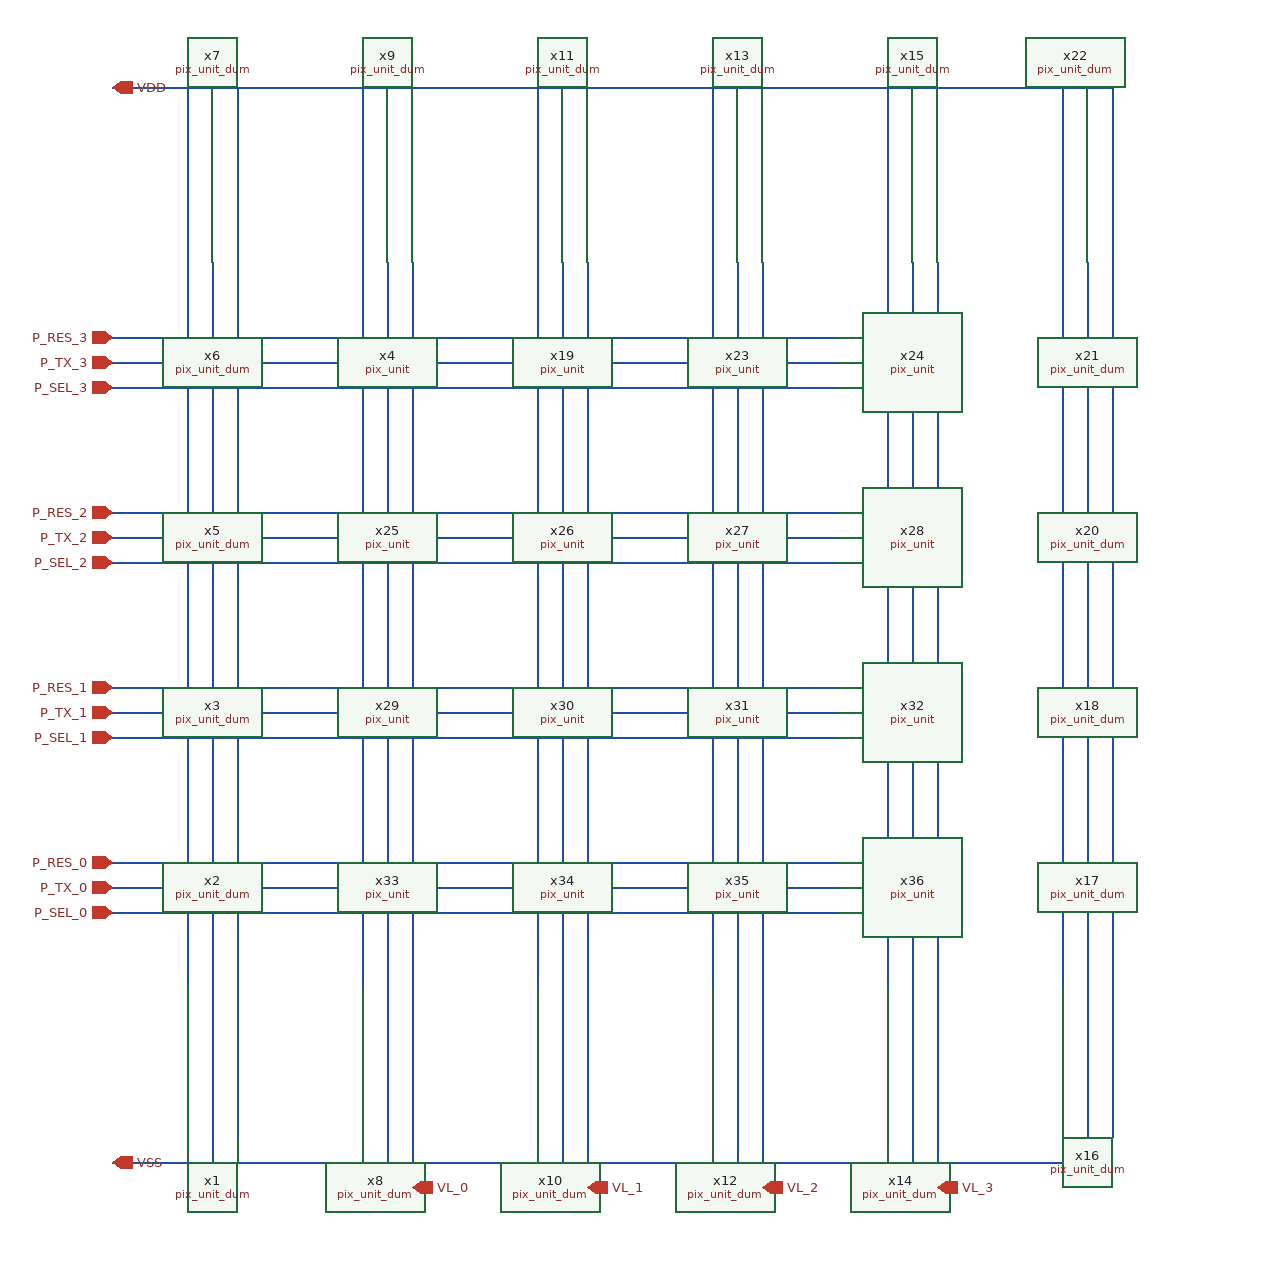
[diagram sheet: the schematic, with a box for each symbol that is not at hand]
v {xschem version=3.4.8RC file_version=1.2}
G {}
K {}
V {}
S {}
E {}
N 180 -960 180 -240 {lab=VDD}
N 320 -960 320 -240 {lab=VDD}
N 460 -960 460 -240 {lab=VDD}
N 600 -960 600 -240 {lab=VDD}
N 740 -960 740 -240 {lab=VDD}
N 880 -960 880 -240 {lab=VDD}
N 120 -960 920 -960 {lab=VDD}
N 200 -820 200 -100 {lab=VSS}
N 340 -820 340 -100 {lab=VSS}
N 480 -820 480 -100 {lab=VSS}
N 620 -820 620 -100 {lab=VSS}
N 760 -820 760 -100 {lab=VSS}
N 900 -820 900 -100 {lab=VSS}
N 120 -100 900 -100 {lab=VSS}
N 220 -960 220 -120 {lab=VDD}
N 920 -960 920 -120 {lab=VDD}
N 360 -820 360 -80 {lab=VL_0}
N 500 -820 500 -80 {lab=VL_1}
N 640 -820 640 -80 {lab=VL_2}
N 780 -820 780 -80 {lab=VL_3}
N 120 -760 700 -760 {lab=P_RES_3}
N 120 -740 700 -740 {lab=P_TX_3}
N 120 -720 700 -720 {lab=P_SEL_3}
N 120 -620 700 -620 {lab=P_RES_2}
N 120 -600 700 -600 {lab=P_TX_2}
N 120 -580 700 -580 {lab=P_SEL_2}
N 120 -480 700 -480 {lab=P_RES_1}
N 120 -460 700 -460 {lab=P_TX_1}
N 120 -440 700 -440 {lab=P_SEL_1}
N 120 -340 700 -340 {lab=P_RES_0}
N 120 -320 700 -320 {lab=P_TX_0}
N 120 -300 700 -300 {lab=P_SEL_0}
C {2026_imager/pix_unit_dum.sym} 200 -180 0 0 {name=x1}
C {2026_imager/pix_unit_dum.sym} 200 -320 0 0 {name=x2}
C {2026_imager/pix_unit_dum.sym} 200 -460 0 0 {name=x3}
C {2026_imager/pix_unit_dum.sym} 200 -600 0 0 {name=x5}
C {2026_imager/pix_unit_dum.sym} 200 -740 0 0 {name=x6}
C {2026_imager/pix_unit_dum.sym} 200 -880 0 0 {name=x7}
C {2026_imager/pix_unit_dum.sym} 340 -180 0 0 {name=x8}
C {2026_imager/pix_unit_dum.sym} 340 -880 0 0 {name=x9}
C {2026_imager/pix_unit_dum.sym} 480 -180 0 0 {name=x10}
C {2026_imager/pix_unit_dum.sym} 480 -880 0 0 {name=x11}
C {2026_imager/pix_unit_dum.sym} 620 -180 0 0 {name=x12}
C {2026_imager/pix_unit_dum.sym} 620 -880 0 0 {name=x13}
C {2026_imager/pix_unit_dum.sym} 760 -180 0 0 {name=x14}
C {2026_imager/pix_unit_dum.sym} 760 -880 0 0 {name=x15}
C {2026_imager/pix_unit_dum.sym} 900 -180 0 0 {name=x16}
C {2026_imager/pix_unit_dum.sym} 900 -320 0 0 {name=x17}
C {2026_imager/pix_unit_dum.sym} 900 -460 0 0 {name=x18}
C {2026_imager/pix_unit_dum.sym} 900 -600 0 0 {name=x20}
C {2026_imager/pix_unit_dum.sym} 900 -740 0 0 {name=x21}
C {2026_imager/pix_unit_dum.sym} 900 -880 0 0 {name=x22}
C {2026_imager/pix_unit.sym} 340 -740 0 0 {name=x4}
C {2026_imager/pix_unit.sym} 480 -740 0 0 {name=x19}
C {2026_imager/pix_unit.sym} 620 -740 0 0 {name=x23}
C {2026_imager/pix_unit.sym} 760 -740 0 0 {name=x24}
C {2026_imager/pix_unit.sym} 340 -600 0 0 {name=x25}
C {2026_imager/pix_unit.sym} 480 -600 0 0 {name=x26}
C {2026_imager/pix_unit.sym} 620 -600 0 0 {name=x27}
C {2026_imager/pix_unit.sym} 760 -600 0 0 {name=x28}
C {2026_imager/pix_unit.sym} 340 -460 0 0 {name=x29}
C {2026_imager/pix_unit.sym} 480 -460 0 0 {name=x30}
C {2026_imager/pix_unit.sym} 620 -460 0 0 {name=x31}
C {2026_imager/pix_unit.sym} 760 -460 0 0 {name=x32}
C {2026_imager/pix_unit.sym} 340 -320 0 0 {name=x33}
C {2026_imager/pix_unit.sym} 480 -320 0 0 {name=x34}
C {2026_imager/pix_unit.sym} 620 -320 0 0 {name=x35}
C {2026_imager/pix_unit.sym} 760 -320 0 0 {name=x36}
C {devices/iopin.sym} 120 -960 0 1 {name=p1 lab=VDD}
C {devices/iopin.sym} 120 -100 0 1 {name=p2 lab=VSS}
C {devices/ipin.sym} 120 -340 0 0 {name=p3 lab=P_RES_0}
C {devices/ipin.sym} 120 -320 0 0 {name=p4 lab=P_TX_0}
C {devices/ipin.sym} 120 -300 0 0 {name=p5 lab=P_SEL_0}
C {devices/ipin.sym} 120 -480 0 0 {name=p6 lab=P_RES_1}
C {devices/ipin.sym} 120 -460 0 0 {name=p7 lab=P_TX_1}
C {devices/ipin.sym} 120 -440 0 0 {name=p8 lab=P_SEL_1}
C {devices/ipin.sym} 120 -620 0 0 {name=p9 lab=P_RES_2}
C {devices/ipin.sym} 120 -600 0 0 {name=p10 lab=P_TX_2}
C {devices/ipin.sym} 120 -580 0 0 {name=p11 lab=P_SEL_2}
C {devices/ipin.sym} 120 -760 0 0 {name=p12 lab=P_RES_3}
C {devices/ipin.sym} 120 -740 0 0 {name=p13 lab=P_TX_3}
C {devices/ipin.sym} 120 -720 0 0 {name=p14 lab=P_SEL_3}
C {devices/opin.sym} 360 -80 1 0 {name=p15 lab=VL_0}
C {devices/opin.sym} 500 -80 1 0 {name=p16 lab=VL_1}
C {devices/opin.sym} 640 -80 1 0 {name=p17 lab=VL_2}
C {devices/opin.sym} 780 -80 1 0 {name=p18 lab=VL_3}
